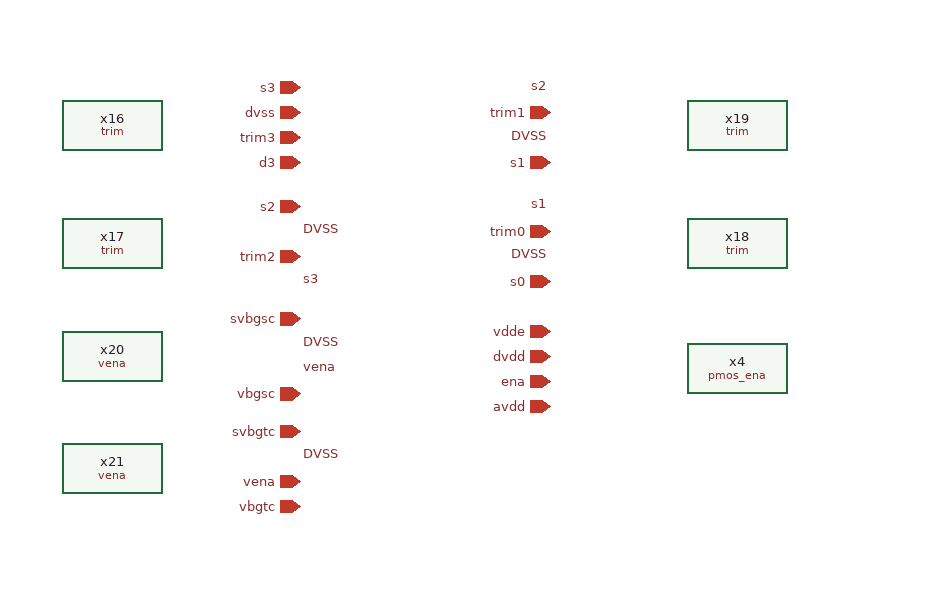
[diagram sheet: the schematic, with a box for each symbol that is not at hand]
v {xschem version=3.4.5 file_version=1.2
}
G {}
K {}
V {}
S {}
E {}
C {/home/gilang_fajrul/chipalooza/sky130_gff_ip__bgr_1.2v/magic/trim.sym} 940 -500 2 0 {name=x18}
C {/home/gilang_fajrul/chipalooza/sky130_gff_ip__bgr_1.2v/magic/trim.sym} 940 -595 2 0 {name=x19}
C {devices/lab_pin.sym} 790 -585 0 0 {name=p71 sig_type=std_logic lab=DVSS}
C {devices/iopin.sym} 790 -605 2 0 {name=p66 lab=trim1}
C {devices/iopin.sym} 790 -510 2 0 {name=p67 lab=trim0}
C {/home/gilang_fajrul/chipalooza/sky130_gff_ip__bgr_1.2v/magic/trim.sym} 440 -595 0 0 {name=x16}
C {/home/gilang_fajrul/chipalooza/sky130_gff_ip__bgr_1.2v/magic/trim.sym} 440 -500 0 0 {name=x17}
C {devices/lab_pin.sym} 590 -510 2 0 {name=p69 sig_type=std_logic lab=DVSS}
C {/home/gilang_fajrul/chipalooza/sky130_gff_ip__bgr_1.2v/magic/vena.sym} 440 -410 0 0 {name=x20}
C {/home/gilang_fajrul/chipalooza/sky130_gff_ip__bgr_1.2v/magic/vena.sym} 440 -320 0 0 {name=x21}
C {devices/lab_pin.sym} 590 -420 2 0 {name=p88 sig_type=std_logic lab=DVSS}
C {devices/lab_pin.sym} 590 -330 2 0 {name=p89 sig_type=std_logic lab=DVSS}
C {devices/iopin.sym} 590 -585 0 0 {name=p34 lab=trim3}
C {devices/iopin.sym} 590 -490 0 0 {name=p65 lab=trim2}
C {devices/iopin.sym} 590 -380 0 0 {name=p72 lab=vbgsc}
C {devices/iopin.sym} 590 -290 0 0 {name=p73 lab=vbgtc}
C {devices/iopin.sym} 590 -310 0 0 {name=p78 lab=vena}
C {devices/lab_pin.sym} 590 -400 2 0 {name=p74 sig_type=std_logic lab=vena}
C {/home/gilang_fajrul/chipalooza/sky130_gff_ip__bgr_1.2v/magic/pmos_ena.sym} 940 -400 2 0 {name=x4}
C {devices/iopin.sym} 790 -370 2 0 {name=p64 lab=avdd}
C {devices/iopin.sym} 790 -410 2 0 {name=p32 lab=dvdd}
C {devices/iopin.sym} 790 -390 2 0 {name=p33 lab=ena}
C {devices/iopin.sym} 590 -605 0 0 {name=p1 lab=dvss}
C {devices/iopin.sym} 590 -625 0 0 {name=p3 lab=s3}
C {devices/iopin.sym} 590 -565 0 0 {name=p4 lab=d3}
C {devices/iopin.sym} 590 -530 0 0 {name=p5 lab=s2}
C {devices/iopin.sym} 790 -470 2 0 {name=p8 lab=s0}
C {devices/iopin.sym} 790 -565 2 0 {name=p10 lab=s1}
C {devices/iopin.sym} 790 -430 2 0 {name=p2 lab=vdde}
C {devices/iopin.sym} 590 -440 0 0 {name=p11 lab=svbgsc}
C {devices/iopin.sym} 590 -350 0 0 {name=p12 lab=svbgtc}
C {devices/lab_pin.sym} 790 -530 0 0 {name=p7 sig_type=std_logic lab=s1}
C {devices/lab_pin.sym} 790 -625 0 0 {name=p9 sig_type=std_logic lab=s2}
C {devices/lab_pin.sym} 590 -470 2 0 {name=p6 sig_type=std_logic lab=s3}
C {devices/lab_pin.sym} 790 -490 0 0 {name=p13 sig_type=std_logic lab=DVSS}
